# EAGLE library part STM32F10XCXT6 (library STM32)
ST STM32F101/103 48pin LQFP

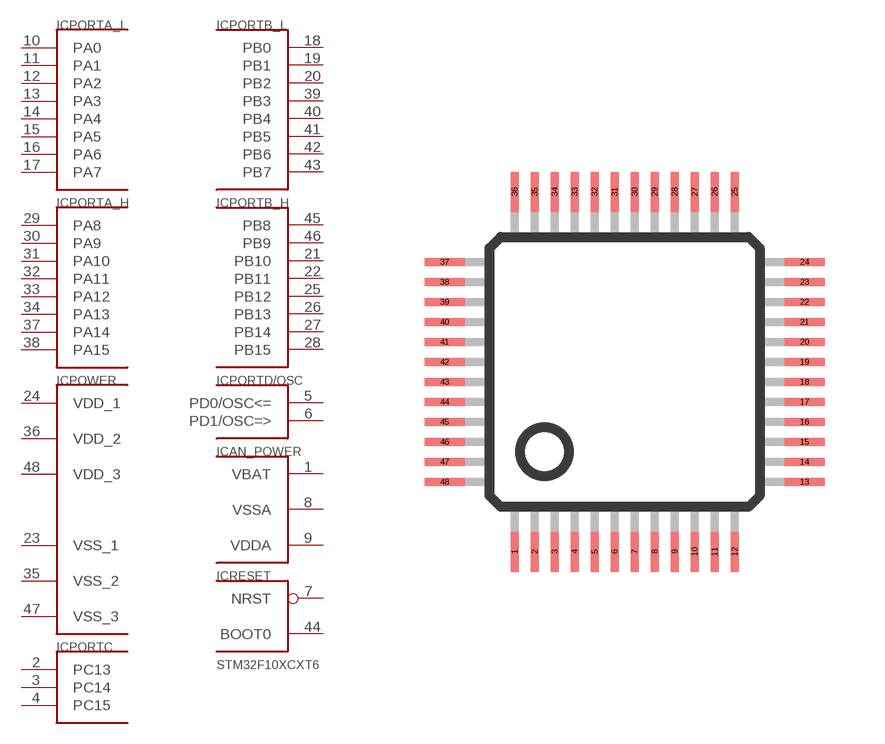
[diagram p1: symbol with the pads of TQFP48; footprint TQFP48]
Designator prefix IC; gates PORTA_L=PORT_A_L PORTA_H=PORT_A_H PORTB_L=PORT_B_L PORTB_H=PORT_B_H POWER=VCC_VDD_S PORTC=PORT_C_3 PORTD/OSC=PORT_D_2 AN_POWER=BAT_AN_M RESET=BOOT_RST

## STM32F10XCXT6  [TQFP48]
1  AN_POWER:VBAT  pwr
2  PORTC:PC13
3  PORTC:PC14
4  PORTC:PC15
5  PORTD/OSC:PD0/OSC<=
6  PORTD/OSC:PD1/OSC=>
7  RESET:NRST  in
8  AN_POWER:VSSA  pwr
9  AN_POWER:VDDA  pwr
10  PORTA_L:PA0
11  PORTA_L:PA1
12  PORTA_L:PA2
13  PORTA_L:PA3
14  PORTA_L:PA4
15  PORTA_L:PA5
16  PORTA_L:PA6
17  PORTA_L:PA7
18  PORTB_L:PB0
19  PORTB_L:PB1
20  PORTB_L:PB2
21  PORTB_H:PB10
22  PORTB_H:PB11
23  POWER:VSS_1  pwr
24  POWER:VDD_1  pwr
25  PORTB_H:PB12
26  PORTB_H:PB13
27  PORTB_H:PB14
28  PORTB_H:PB15
29  PORTA_H:PA8
30  PORTA_H:PA9
31  PORTA_H:PA10
32  PORTA_H:PA11
33  PORTA_H:PA12
34  PORTA_H:PA13
35  POWER:VSS_2  pwr
36  POWER:VDD_2  pwr
37  PORTA_H:PA14
38  PORTA_H:PA15
39  PORTB_L:PB3
40  PORTB_L:PB4
41  PORTB_L:PB5
42  PORTB_L:PB6
43  PORTB_L:PB7
44  RESET:BOOT0  in
45  PORTB_H:PB8
46  PORTB_H:PB9
47  POWER:VSS_3  pwr
48  POWER:VDD_3  pwr

## Footprint TQFP48 (pad centres in mm)
smd 0.2 x 1: 1 -2.75,-4.5; 2 -2.25,-4.5; 3 -1.75,-4.5; 4 -1.25,-4.5; 5 -0.75,-4.5; 6 -0.25,-4.5; 7 0.25,-4.5; 8 0.75,-4.5; 9 1.25,-4.5; 10 1.75,-4.5; 11 2.25,-4.5; 12 2.75,-4.5; 25 2.75,4.5; 26 2.25,4.5; 27 1.75,4.5; 28 1.25,4.5; 29 0.75,4.5; 30 0.25,4.5; 31 -0.25,4.5; 32 -0.75,4.5; 33 -1.25,4.5; 34 -1.75,4.5; 35 -2.25,4.5; 36 -2.75,4.5
smd 1 x 0.2: 13 4.5,-2.75; 14 4.5,-2.25; 15 4.5,-1.75; 16 4.5,-1.25; 17 4.5,-0.75; 18 4.5,-0.25; 19 4.5,0.25; 20 4.5,0.75; 21 4.5,1.25; 22 4.5,1.75; 23 4.5,2.25; 24 4.5,2.75; 37 -4.5,2.75; 38 -4.5,2.25; 39 -4.5,1.75; 40 -4.5,1.25; 41 -4.5,0.75; 42 -4.5,0.25; 43 -4.5,-0.25; 44 -4.5,-0.75; 45 -4.5,-1.25; 46 -4.5,-1.75; 47 -4.5,-2.25; 48 -4.5,-2.75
